VERSION 5.7 ;
  NOWIREEXTENSIONATPIN ON ;
  DIVIDERCHAR "/" ;
  BUSBITCHARS "[]" ;
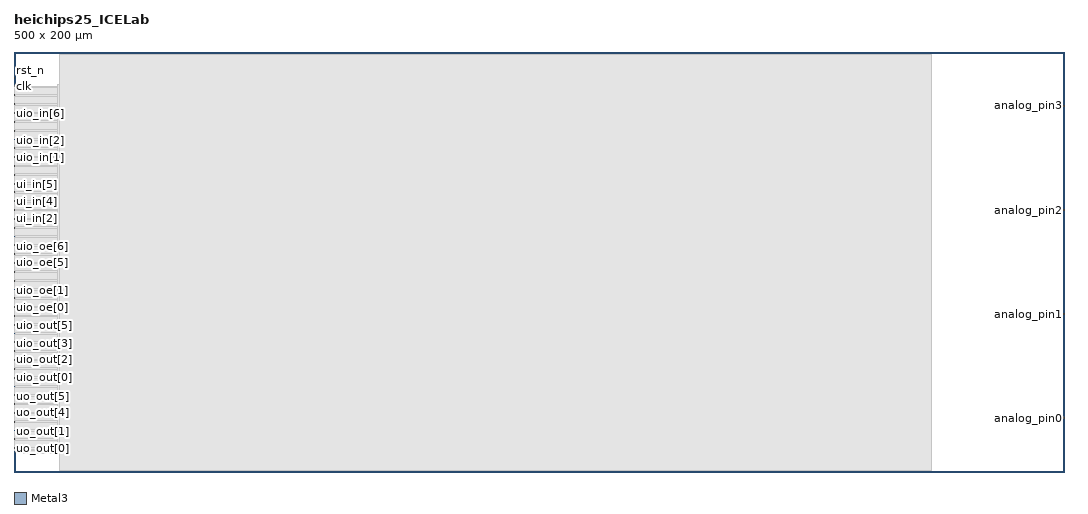
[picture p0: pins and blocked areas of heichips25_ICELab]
MACRO heichips25_ICELab
  CLASS BLOCK ;
  FOREIGN heichips25_ICELab ;
  ORIGIN 0.000 0.000 ;
  SIZE 500.000 BY 200.000 ;
  PIN analog_pin0
    DIRECTION INOUT ;
    USE SIGNAL ;
    PORT
      LAYER Metal3 ;
        RECT 499.600 25.420 500.000 25.820 ;
    END
  END analog_pin0
  PIN analog_pin1
    DIRECTION INOUT ;
    USE SIGNAL ;
    PORT
      LAYER Metal3 ;
        RECT 499.600 74.980 500.000 75.380 ;
    END
  END analog_pin1
  PIN analog_pin2
    DIRECTION INOUT ;
    USE SIGNAL ;
    PORT
      LAYER Metal3 ;
        RECT 499.600 124.540 500.000 124.940 ;
    END
  END analog_pin2
  PIN analog_pin3
    DIRECTION INOUT ;
    USE SIGNAL ;
    PORT
      LAYER Metal3 ;
        RECT 499.600 174.100 500.000 174.500 ;
    END
  END analog_pin3
  PIN clk
    DIRECTION INPUT ;
    USE SIGNAL ;
    ANTENNAGATEAREA 4.836000 ;
    PORT
      LAYER Metal3 ;
        RECT 0.000 183.340 0.400 183.740 ;
    END
  END clk
  PIN ena
    DIRECTION INPUT ;
    USE SIGNAL ;
    ANTENNAGATEAREA 14.774400 ;
    PORT
      LAYER Metal3 ;
        RECT 0.000 179.140 0.400 179.540 ;
    END
  END ena
  PIN rst_n
    DIRECTION INPUT ;
    USE SIGNAL ;
    PORT
      LAYER Metal3 ;
        RECT 0.000 187.540 0.400 187.940 ;
    END
  END rst_n
  PIN ui_in[0]
    DIRECTION INPUT ;
    USE SIGNAL ;
    ANTENNAGATEAREA 1.310400 ;
    PORT
      LAYER Metal3 ;
        RECT 0.000 111.940 0.400 112.340 ;
    END
  END ui_in[0]
  PIN ui_in[1]
    DIRECTION INPUT ;
    USE SIGNAL ;
    ANTENNAGATEAREA 1.310400 ;
    PORT
      LAYER Metal3 ;
        RECT 0.000 116.140 0.400 116.540 ;
    END
  END ui_in[1]
  PIN ui_in[2]
    DIRECTION INPUT ;
    USE SIGNAL ;
    ANTENNAGATEAREA 5.241600 ;
    PORT
      LAYER Metal3 ;
        RECT 0.000 120.340 0.400 120.740 ;
    END
  END ui_in[2]
  PIN ui_in[3]
    DIRECTION INPUT ;
    USE SIGNAL ;
    ANTENNAGATEAREA 5.241600 ;
    PORT
      LAYER Metal3 ;
        RECT 0.000 124.540 0.400 124.940 ;
    END
  END ui_in[3]
  PIN ui_in[4]
    DIRECTION INPUT ;
    USE SIGNAL ;
    ANTENNAGATEAREA 20.966400 ;
    PORT
      LAYER Metal3 ;
        RECT 0.000 128.740 0.400 129.140 ;
    END
  END ui_in[4]
  PIN ui_in[5]
    DIRECTION INPUT ;
    USE SIGNAL ;
    ANTENNAGATEAREA 20.966400 ;
    PORT
      LAYER Metal3 ;
        RECT 0.000 132.940 0.400 133.340 ;
    END
  END ui_in[5]
  PIN ui_in[6]
    DIRECTION INPUT ;
    USE SIGNAL ;
    ANTENNAGATEAREA 0.445200 ;
    PORT
      LAYER Metal3 ;
        RECT 0.000 137.140 0.400 137.540 ;
    END
  END ui_in[6]
  PIN ui_in[7]
    DIRECTION INPUT ;
    USE SIGNAL ;
    ANTENNAGATEAREA 0.445200 ;
    PORT
      LAYER Metal3 ;
        RECT 0.000 141.340 0.400 141.740 ;
    END
  END ui_in[7]
  PIN uio_in[0]
    DIRECTION INPUT ;
    USE SIGNAL ;
    ANTENNAGATEAREA 1.310400 ;
    PORT
      LAYER Metal3 ;
        RECT 0.000 145.540 0.400 145.940 ;
    END
  END uio_in[0]
  PIN uio_in[1]
    DIRECTION INPUT ;
    USE SIGNAL ;
    ANTENNAGATEAREA 1.310400 ;
    PORT
      LAYER Metal3 ;
        RECT 0.000 149.740 0.400 150.140 ;
    END
  END uio_in[1]
  PIN uio_in[2]
    DIRECTION INPUT ;
    USE SIGNAL ;
    ANTENNAGATEAREA 0.327600 ;
    PORT
      LAYER Metal3 ;
        RECT 0.000 153.940 0.400 154.340 ;
    END
  END uio_in[2]
  PIN uio_in[3]
    DIRECTION INPUT ;
    USE SIGNAL ;
    ANTENNAGATEAREA 9.828000 ;
    PORT
      LAYER Metal3 ;
        RECT 0.000 158.140 0.400 158.540 ;
    END
  END uio_in[3]
  PIN uio_in[4]
    DIRECTION INPUT ;
    USE SIGNAL ;
    ANTENNAGATEAREA 3.868800 ;
    PORT
      LAYER Metal3 ;
        RECT 0.000 162.340 0.400 162.740 ;
    END
  END uio_in[4]
  PIN uio_in[5]
    DIRECTION INPUT ;
    USE SIGNAL ;
    ANTENNAGATEAREA 0.967200 ;
    PORT
      LAYER Metal3 ;
        RECT 0.000 166.540 0.400 166.940 ;
    END
  END uio_in[5]
  PIN uio_in[6]
    DIRECTION INPUT ;
    USE SIGNAL ;
    ANTENNAGATEAREA 0.384800 ;
    PORT
      LAYER Metal3 ;
        RECT 0.000 170.740 0.400 171.140 ;
    END
  END uio_in[6]
  PIN uio_in[7]
    DIRECTION INPUT ;
    USE SIGNAL ;
    PORT
      LAYER Metal3 ;
        RECT 0.000 174.940 0.400 175.340 ;
    END
  END uio_in[7]
  PIN uio_oe[0]
    DIRECTION OUTPUT ;
    USE SIGNAL ;
    PORT
      LAYER Metal3 ;
        RECT 0.000 78.340 0.400 78.740 ;
    END
  END uio_oe[0]
  PIN uio_oe[1]
    DIRECTION OUTPUT ;
    USE SIGNAL ;
    PORT
      LAYER Metal3 ;
        RECT 0.000 82.540 0.400 82.940 ;
    END
  END uio_oe[1]
  PIN uio_oe[2]
    DIRECTION OUTPUT ;
    USE SIGNAL ;
    PORT
      LAYER Metal3 ;
        RECT 0.000 86.740 0.400 87.140 ;
    END
  END uio_oe[2]
  PIN uio_oe[3]
    DIRECTION OUTPUT ;
    USE SIGNAL ;
    PORT
      LAYER Metal3 ;
        RECT 0.000 90.940 0.400 91.340 ;
    END
  END uio_oe[3]
  PIN uio_oe[4]
    DIRECTION OUTPUT ;
    USE SIGNAL ;
    PORT
      LAYER Metal3 ;
        RECT 0.000 95.140 0.400 95.540 ;
    END
  END uio_oe[4]
  PIN uio_oe[5]
    DIRECTION OUTPUT ;
    USE SIGNAL ;
    PORT
      LAYER Metal3 ;
        RECT 0.000 99.340 0.400 99.740 ;
    END
  END uio_oe[5]
  PIN uio_oe[6]
    DIRECTION OUTPUT ;
    USE SIGNAL ;
    PORT
      LAYER Metal3 ;
        RECT 0.000 103.540 0.400 103.940 ;
    END
  END uio_oe[6]
  PIN uio_oe[7]
    DIRECTION OUTPUT ;
    USE SIGNAL ;
    PORT
      LAYER Metal3 ;
        RECT 0.000 107.740 0.400 108.140 ;
    END
  END uio_oe[7]
  PIN uio_out[0]
    DIRECTION OUTPUT ;
    USE SIGNAL ;
    PORT
      LAYER Metal3 ;
        RECT 0.000 44.740 0.400 45.140 ;
    END
  END uio_out[0]
  PIN uio_out[1]
    DIRECTION OUTPUT ;
    USE SIGNAL ;
    PORT
      LAYER Metal3 ;
        RECT 0.000 48.940 0.400 49.340 ;
    END
  END uio_out[1]
  PIN uio_out[2]
    DIRECTION OUTPUT ;
    USE SIGNAL ;
    PORT
      LAYER Metal3 ;
        RECT 0.000 53.140 0.400 53.540 ;
    END
  END uio_out[2]
  PIN uio_out[3]
    DIRECTION OUTPUT ;
    USE SIGNAL ;
    PORT
      LAYER Metal3 ;
        RECT 0.000 57.340 0.400 57.740 ;
    END
  END uio_out[3]
  PIN uio_out[4]
    DIRECTION OUTPUT ;
    USE SIGNAL ;
    PORT
      LAYER Metal3 ;
        RECT 0.000 61.540 0.400 61.940 ;
    END
  END uio_out[4]
  PIN uio_out[5]
    DIRECTION OUTPUT ;
    USE SIGNAL ;
    PORT
      LAYER Metal3 ;
        RECT 0.000 65.740 0.400 66.140 ;
    END
  END uio_out[5]
  PIN uio_out[6]
    DIRECTION OUTPUT ;
    USE SIGNAL ;
    PORT
      LAYER Metal3 ;
        RECT 0.000 69.940 0.400 70.340 ;
    END
  END uio_out[6]
  PIN uio_out[7]
    DIRECTION OUTPUT ;
    USE SIGNAL ;
    PORT
      LAYER Metal3 ;
        RECT 0.000 74.140 0.400 74.540 ;
    END
  END uio_out[7]
  PIN uo_out[0]
    DIRECTION OUTPUT ;
    USE SIGNAL ;
    PORT
      LAYER Metal3 ;
        RECT 0.000 11.140 0.400 11.540 ;
    END
  END uo_out[0]
  PIN uo_out[1]
    DIRECTION OUTPUT ;
    USE SIGNAL ;
    PORT
      LAYER Metal3 ;
        RECT 0.000 15.340 0.400 15.740 ;
    END
  END uo_out[1]
  PIN uo_out[2]
    DIRECTION OUTPUT ;
    USE SIGNAL ;
    PORT
      LAYER Metal3 ;
        RECT 0.000 19.540 0.400 19.940 ;
    END
  END uo_out[2]
  PIN uo_out[3]
    DIRECTION OUTPUT ;
    USE SIGNAL ;
    PORT
      LAYER Metal3 ;
        RECT 0.000 23.740 0.400 24.140 ;
    END
  END uo_out[3]
  PIN uo_out[4]
    DIRECTION OUTPUT ;
    USE SIGNAL ;
    PORT
      LAYER Metal3 ;
        RECT 0.000 27.940 0.400 28.340 ;
    END
  END uo_out[4]
  PIN uo_out[5]
    DIRECTION OUTPUT ;
    USE SIGNAL ;
    PORT
      LAYER Metal3 ;
        RECT 0.000 32.140 0.400 32.540 ;
    END
  END uo_out[5]
  PIN uo_out[6]
    DIRECTION OUTPUT ;
    USE SIGNAL ;
    PORT
      LAYER Metal3 ;
        RECT 0.000 36.340 0.400 36.740 ;
    END
  END uo_out[6]
  PIN uo_out[7]
    DIRECTION OUTPUT ;
    USE SIGNAL ;
    PORT
      LAYER Metal3 ;
        RECT 0.000 40.540 0.400 40.940 ;
    END
  END uo_out[7]
  OBS
      LAYER GatPoly ;
        RECT 10.150 10.160 258.130 175.400 ;
      LAYER Metal1 ;
        RECT 9.910 10.250 258.130 175.110 ;
      LAYER Metal2 ;
        RECT 4.450 8.610 257.940 183.740 ;
      LAYER Metal3 ;
        RECT 0.610 183.130 258.370 183.740 ;
        RECT 0.360 179.750 258.370 183.130 ;
        RECT 0.610 178.930 258.370 179.750 ;
        RECT 0.360 175.550 258.370 178.930 ;
        RECT 0.610 174.730 258.370 175.550 ;
        RECT 0.360 171.350 258.370 174.730 ;
        RECT 0.610 170.530 258.370 171.350 ;
        RECT 0.360 167.150 258.370 170.530 ;
        RECT 0.610 166.330 258.370 167.150 ;
        RECT 0.360 162.950 258.370 166.330 ;
        RECT 0.610 162.130 258.370 162.950 ;
        RECT 0.360 158.750 258.370 162.130 ;
        RECT 0.610 157.930 258.370 158.750 ;
        RECT 0.360 154.550 258.370 157.930 ;
        RECT 0.610 153.730 258.370 154.550 ;
        RECT 0.360 150.350 258.370 153.730 ;
        RECT 0.610 149.530 258.370 150.350 ;
        RECT 0.360 146.150 258.370 149.530 ;
        RECT 0.610 145.330 258.370 146.150 ;
        RECT 0.360 141.950 258.370 145.330 ;
        RECT 0.610 141.130 258.370 141.950 ;
        RECT 0.360 137.750 258.370 141.130 ;
        RECT 0.610 136.930 258.370 137.750 ;
        RECT 0.360 133.550 258.370 136.930 ;
        RECT 0.610 132.730 258.370 133.550 ;
        RECT 0.360 129.350 258.370 132.730 ;
        RECT 0.610 128.530 258.370 129.350 ;
        RECT 0.360 125.150 258.370 128.530 ;
        RECT 0.610 124.330 258.370 125.150 ;
        RECT 0.360 120.950 258.370 124.330 ;
        RECT 0.610 120.130 258.370 120.950 ;
        RECT 0.360 116.750 258.370 120.130 ;
        RECT 0.610 115.930 258.370 116.750 ;
        RECT 0.360 112.550 258.370 115.930 ;
        RECT 0.610 111.730 258.370 112.550 ;
        RECT 0.360 108.350 258.370 111.730 ;
        RECT 0.610 107.530 258.370 108.350 ;
        RECT 0.360 104.150 258.370 107.530 ;
        RECT 0.610 103.330 258.370 104.150 ;
        RECT 0.360 99.950 258.370 103.330 ;
        RECT 0.610 99.130 258.370 99.950 ;
        RECT 0.360 95.750 258.370 99.130 ;
        RECT 0.610 94.930 258.370 95.750 ;
        RECT 0.360 91.550 258.370 94.930 ;
        RECT 0.610 90.730 258.370 91.550 ;
        RECT 0.360 87.350 258.370 90.730 ;
        RECT 0.610 86.530 258.370 87.350 ;
        RECT 0.360 83.150 258.370 86.530 ;
        RECT 0.610 82.330 258.370 83.150 ;
        RECT 0.360 78.950 258.370 82.330 ;
        RECT 0.610 78.130 258.370 78.950 ;
        RECT 0.360 74.750 258.370 78.130 ;
        RECT 0.610 73.930 258.370 74.750 ;
        RECT 0.360 70.550 258.370 73.930 ;
        RECT 0.610 69.730 258.370 70.550 ;
        RECT 0.360 66.350 258.370 69.730 ;
        RECT 0.610 65.530 258.370 66.350 ;
        RECT 0.360 62.150 258.370 65.530 ;
        RECT 0.610 61.330 258.370 62.150 ;
        RECT 0.360 57.950 258.370 61.330 ;
        RECT 0.610 57.130 258.370 57.950 ;
        RECT 0.360 53.750 258.370 57.130 ;
        RECT 0.610 52.930 258.370 53.750 ;
        RECT 0.360 49.550 258.370 52.930 ;
        RECT 0.610 48.730 258.370 49.550 ;
        RECT 0.360 45.350 258.370 48.730 ;
        RECT 0.610 44.530 258.370 45.350 ;
        RECT 0.360 41.150 258.370 44.530 ;
        RECT 0.610 40.330 258.370 41.150 ;
        RECT 0.360 36.950 258.370 40.330 ;
        RECT 0.610 36.130 258.370 36.950 ;
        RECT 0.360 32.750 258.370 36.130 ;
        RECT 0.610 31.930 258.370 32.750 ;
        RECT 0.360 28.550 258.370 31.930 ;
        RECT 0.610 27.730 258.370 28.550 ;
        RECT 0.360 24.350 258.370 27.730 ;
        RECT 0.610 23.530 258.370 24.350 ;
        RECT 0.360 20.150 258.370 23.530 ;
        RECT 0.610 19.330 258.370 20.150 ;
        RECT 0.360 15.950 258.370 19.330 ;
        RECT 0.610 15.130 258.370 15.950 ;
        RECT 0.360 11.750 258.370 15.130 ;
        RECT 0.610 10.930 258.370 11.750 ;
        RECT 0.360 10.360 258.370 10.930 ;
      LAYER Metal4 ;
        RECT 22.340 20.210 58.600 175.760 ;
      LAYER Metal5 ;
        RECT 20.660 11.140 71.740 184.730 ;
      LAYER TopMetal1 ;
        RECT 21.605 0.770 436.960 198.770 ;
  END
END heichips25_ICELab
END LIBRARY

